VERSION 5.8 ;
BUSBITCHARS "[]" ;
DIVIDERCHAR "/" ;
UNITS
    DATABASE MICRONS 1000 ;
END UNITS

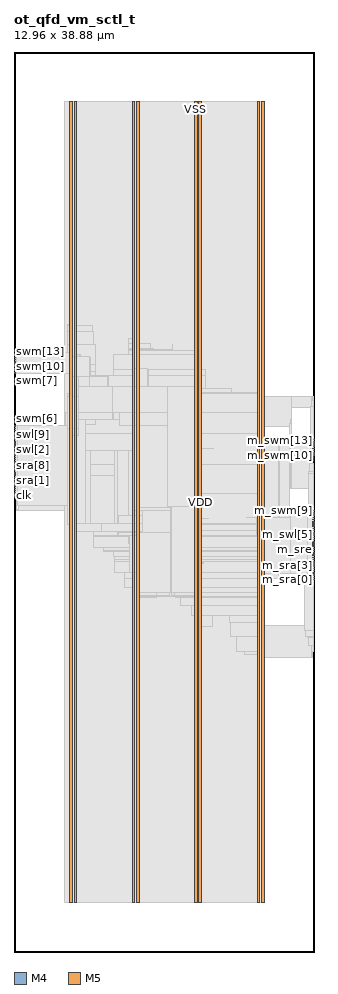
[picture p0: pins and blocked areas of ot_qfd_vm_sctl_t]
MACRO ot_qfd_vm_sctl_t
  FOREIGN ot_qfd_vm_sctl_t 0 0 ;
  CLASS BLOCK ;
  SIZE 12.96 BY 38.88 ;
  PIN clk
    DIRECTION INPUT ;
    USE SIGNAL ;
    PORT
      LAYER M4 ;
        RECT  0 19.728 0.084 19.752 ;
    END
  END clk
  PIN m_sra[0]
    DIRECTION OUTPUT ;
    USE SIGNAL ;
    PORT
      LAYER M4 ;
        RECT  12.876 16.08 12.96 16.104 ;
    END
  END m_sra[0]
  PIN m_sra[1]
    DIRECTION OUTPUT ;
    USE SIGNAL ;
    PORT
      LAYER M4 ;
        RECT  12.876 16.176 12.96 16.2 ;
    END
  END m_sra[1]
  PIN m_sra[2]
    DIRECTION OUTPUT ;
    USE SIGNAL ;
    PORT
      LAYER M4 ;
        RECT  12.876 16.272 12.96 16.296 ;
    END
  END m_sra[2]
  PIN m_sra[3]
    DIRECTION OUTPUT ;
    USE SIGNAL ;
    PORT
      LAYER M4 ;
        RECT  12.876 16.368 12.96 16.392 ;
    END
  END m_sra[3]
  PIN m_sra[4]
    DIRECTION OUTPUT ;
    USE SIGNAL ;
    PORT
      LAYER M4 ;
        RECT  12.876 16.464 12.96 16.488 ;
    END
  END m_sra[4]
  PIN m_sra[5]
    DIRECTION OUTPUT ;
    USE SIGNAL ;
    PORT
      LAYER M4 ;
        RECT  12.876 16.56 12.96 16.584 ;
    END
  END m_sra[5]
  PIN m_sra[6]
    DIRECTION OUTPUT ;
    USE SIGNAL ;
    PORT
      LAYER M4 ;
        RECT  12.876 16.656 12.96 16.68 ;
    END
  END m_sra[6]
  PIN m_sra[7]
    DIRECTION OUTPUT ;
    USE SIGNAL ;
    PORT
      LAYER M4 ;
        RECT  12.876 16.752 12.96 16.776 ;
    END
  END m_sra[7]
  PIN m_sra[8]
    DIRECTION OUTPUT ;
    USE SIGNAL ;
    PORT
      LAYER M4 ;
        RECT  12.876 16.848 12.96 16.872 ;
    END
  END m_sra[8]
  PIN m_sra[9]
    DIRECTION OUTPUT ;
    USE SIGNAL ;
    PORT
      LAYER M4 ;
        RECT  12.876 16.944 12.96 16.968 ;
    END
  END m_sra[9]
  PIN m_sre
    DIRECTION OUTPUT ;
    USE SIGNAL ;
    PORT
      LAYER M4 ;
        RECT  12.876 17.04 12.96 17.064 ;
    END
  END m_sre
  PIN m_swe
    DIRECTION OUTPUT ;
    USE SIGNAL ;
    PORT
      LAYER M4 ;
        RECT  12.876 17.136 12.96 17.16 ;
    END
  END m_swe
  PIN m_swl[0]
    DIRECTION OUTPUT ;
    USE SIGNAL ;
    PORT
      LAYER M4 ;
        RECT  12.876 17.232 12.96 17.256 ;
    END
  END m_swl[0]
  PIN m_swl[1]
    DIRECTION OUTPUT ;
    USE SIGNAL ;
    PORT
      LAYER M4 ;
        RECT  12.876 17.328 12.96 17.352 ;
    END
  END m_swl[1]
  PIN m_swl[2]
    DIRECTION OUTPUT ;
    USE SIGNAL ;
    PORT
      LAYER M4 ;
        RECT  12.876 17.424 12.96 17.448 ;
    END
  END m_swl[2]
  PIN m_swl[3]
    DIRECTION OUTPUT ;
    USE SIGNAL ;
    PORT
      LAYER M4 ;
        RECT  12.876 17.52 12.96 17.544 ;
    END
  END m_swl[3]
  PIN m_swl[4]
    DIRECTION OUTPUT ;
    USE SIGNAL ;
    PORT
      LAYER M4 ;
        RECT  12.876 17.616 12.96 17.64 ;
    END
  END m_swl[4]
  PIN m_swl[5]
    DIRECTION OUTPUT ;
    USE SIGNAL ;
    PORT
      LAYER M4 ;
        RECT  12.876 17.712 12.96 17.736 ;
    END
  END m_swl[5]
  PIN m_swl[6]
    DIRECTION OUTPUT ;
    USE SIGNAL ;
    PORT
      LAYER M4 ;
        RECT  12.876 17.808 12.96 17.832 ;
    END
  END m_swl[6]
  PIN m_swl[7]
    DIRECTION OUTPUT ;
    USE SIGNAL ;
    PORT
      LAYER M4 ;
        RECT  12.876 17.904 12.96 17.928 ;
    END
  END m_swl[7]
  PIN m_swl[8]
    DIRECTION OUTPUT ;
    USE SIGNAL ;
    PORT
      LAYER M4 ;
        RECT  12.876 18 12.96 18.024 ;
    END
  END m_swl[8]
  PIN m_swl[9]
    DIRECTION OUTPUT ;
    USE SIGNAL ;
    PORT
      LAYER M4 ;
        RECT  12.876 18.096 12.96 18.12 ;
    END
  END m_swl[9]
  PIN m_swm[0]
    DIRECTION OUTPUT ;
    USE SIGNAL ;
    PORT
      LAYER M4 ;
        RECT  12.876 18.192 12.96 18.216 ;
    END
  END m_swm[0]
  PIN m_swm[10]
    DIRECTION OUTPUT ;
    USE SIGNAL ;
    PORT
      LAYER M4 ;
        RECT  12.876 21.456 12.96 21.48 ;
    END
  END m_swm[10]
  PIN m_swm[11]
    DIRECTION OUTPUT ;
    USE SIGNAL ;
    PORT
      LAYER M4 ;
        RECT  12.876 21.552 12.96 21.576 ;
    END
  END m_swm[11]
  PIN m_swm[12]
    DIRECTION OUTPUT ;
    USE SIGNAL ;
    PORT
      LAYER M4 ;
        RECT  12.876 21.648 12.96 21.672 ;
    END
  END m_swm[12]
  PIN m_swm[13]
    DIRECTION OUTPUT ;
    USE SIGNAL ;
    PORT
      LAYER M4 ;
        RECT  12.876 21.744 12.96 21.768 ;
    END
  END m_swm[13]
  PIN m_swm[14]
    DIRECTION OUTPUT ;
    USE SIGNAL ;
    PORT
      LAYER M4 ;
        RECT  12.876 21.84 12.96 21.864 ;
    END
  END m_swm[14]
  PIN m_swm[15]
    DIRECTION OUTPUT ;
    USE SIGNAL ;
    PORT
      LAYER M4 ;
        RECT  12.876 21.936 12.96 21.96 ;
    END
  END m_swm[15]
  PIN m_swm[1]
    DIRECTION OUTPUT ;
    USE SIGNAL ;
    PORT
      LAYER M4 ;
        RECT  12.876 18.288 12.96 18.312 ;
    END
  END m_swm[1]
  PIN m_swm[2]
    DIRECTION OUTPUT ;
    USE SIGNAL ;
    PORT
      LAYER M4 ;
        RECT  12.876 18.384 12.96 18.408 ;
    END
  END m_swm[2]
  PIN m_swm[3]
    DIRECTION OUTPUT ;
    USE SIGNAL ;
    PORT
      LAYER M4 ;
        RECT  12.876 18.48 12.96 18.504 ;
    END
  END m_swm[3]
  PIN m_swm[4]
    DIRECTION OUTPUT ;
    USE SIGNAL ;
    PORT
      LAYER M4 ;
        RECT  12.876 18.576 12.96 18.6 ;
    END
  END m_swm[4]
  PIN m_swm[5]
    DIRECTION OUTPUT ;
    USE SIGNAL ;
    PORT
      LAYER M4 ;
        RECT  12.876 18.672 12.96 18.696 ;
    END
  END m_swm[5]
  PIN m_swm[6]
    DIRECTION OUTPUT ;
    USE SIGNAL ;
    PORT
      LAYER M4 ;
        RECT  12.876 18.768 12.96 18.792 ;
    END
  END m_swm[6]
  PIN m_swm[7]
    DIRECTION OUTPUT ;
    USE SIGNAL ;
    PORT
      LAYER M4 ;
        RECT  12.876 18.864 12.96 18.888 ;
    END
  END m_swm[7]
  PIN m_swm[8]
    DIRECTION OUTPUT ;
    USE SIGNAL ;
    PORT
      LAYER M4 ;
        RECT  12.876 18.96 12.96 18.984 ;
    END
  END m_swm[8]
  PIN m_swm[9]
    DIRECTION OUTPUT ;
    USE SIGNAL ;
    PORT
      LAYER M4 ;
        RECT  12.876 19.056 12.96 19.08 ;
    END
  END m_swm[9]
  PIN rst_n
    DIRECTION INPUT ;
    USE SIGNAL ;
    PORT
      LAYER M4 ;
        RECT  0 19.824 0.084 19.848 ;
    END
  END rst_n
  PIN rtg
    DIRECTION OUTPUT ;
    USE SIGNAL ;
    PORT
      LAYER M4 ;
        RECT  12.876 22.032 12.96 22.056 ;
    END
  END rtg
  PIN sra[0]
    DIRECTION INPUT ;
    USE SIGNAL ;
    PORT
      LAYER M4 ;
        RECT  0 19.92 0.084 19.944 ;
    END
  END sra[0]
  PIN sra[1]
    DIRECTION INPUT ;
    USE SIGNAL ;
    PORT
      LAYER M4 ;
        RECT  0 20.016 0.084 20.04 ;
    END
  END sra[1]
  PIN sra[2]
    DIRECTION INPUT ;
    USE SIGNAL ;
    PORT
      LAYER M4 ;
        RECT  0 20.112 0.084 20.136 ;
    END
  END sra[2]
  PIN sra[3]
    DIRECTION INPUT ;
    USE SIGNAL ;
    PORT
      LAYER M4 ;
        RECT  0 20.208 0.084 20.232 ;
    END
  END sra[3]
  PIN sra[4]
    DIRECTION INPUT ;
    USE SIGNAL ;
    PORT
      LAYER M4 ;
        RECT  0 20.304 0.084 20.328 ;
    END
  END sra[4]
  PIN sra[5]
    DIRECTION INPUT ;
    USE SIGNAL ;
    PORT
      LAYER M4 ;
        RECT  0 20.4 0.084 20.424 ;
    END
  END sra[5]
  PIN sra[6]
    DIRECTION INPUT ;
    USE SIGNAL ;
    PORT
      LAYER M4 ;
        RECT  0 20.496 0.084 20.52 ;
    END
  END sra[6]
  PIN sra[7]
    DIRECTION INPUT ;
    USE SIGNAL ;
    PORT
      LAYER M4 ;
        RECT  0 20.592 0.084 20.616 ;
    END
  END sra[7]
  PIN sra[8]
    DIRECTION INPUT ;
    USE SIGNAL ;
    PORT
      LAYER M4 ;
        RECT  0 20.688 0.084 20.712 ;
    END
  END sra[8]
  PIN sra[9]
    DIRECTION INPUT ;
    USE SIGNAL ;
    PORT
      LAYER M4 ;
        RECT  0 20.784 0.084 20.808 ;
    END
  END sra[9]
  PIN sre
    DIRECTION INPUT ;
    USE SIGNAL ;
    PORT
      LAYER M4 ;
        RECT  0 20.88 0.084 20.904 ;
    END
  END sre
  PIN sv
    DIRECTION INPUT ;
    USE SIGNAL ;
    PORT
      LAYER M4 ;
        RECT  0 20.976 0.084 21 ;
    END
  END sv
  PIN svc
    DIRECTION OUTPUT ;
    USE SIGNAL ;
    PORT
      LAYER M4 ;
        RECT  12.876 22.128 12.96 22.152 ;
    END
  END svc
  PIN swe
    DIRECTION INPUT ;
    USE SIGNAL ;
    PORT
      LAYER M4 ;
        RECT  0 21.072 0.084 21.096 ;
    END
  END swe
  PIN swl[0]
    DIRECTION INPUT ;
    USE SIGNAL ;
    PORT
      LAYER M4 ;
        RECT  0 21.168 0.084 21.192 ;
    END
  END swl[0]
  PIN swl[1]
    DIRECTION INPUT ;
    USE SIGNAL ;
    PORT
      LAYER M4 ;
        RECT  0 21.264 0.084 21.288 ;
    END
  END swl[1]
  PIN swl[2]
    DIRECTION INPUT ;
    USE SIGNAL ;
    PORT
      LAYER M4 ;
        RECT  0 21.36 0.084 21.384 ;
    END
  END swl[2]
  PIN swl[3]
    DIRECTION INPUT ;
    USE SIGNAL ;
    PORT
      LAYER M4 ;
        RECT  0 21.456 0.084 21.48 ;
    END
  END swl[3]
  PIN swl[4]
    DIRECTION INPUT ;
    USE SIGNAL ;
    PORT
      LAYER M4 ;
        RECT  0 21.552 0.084 21.576 ;
    END
  END swl[4]
  PIN swl[5]
    DIRECTION INPUT ;
    USE SIGNAL ;
    PORT
      LAYER M4 ;
        RECT  0 21.648 0.084 21.672 ;
    END
  END swl[5]
  PIN swl[6]
    DIRECTION INPUT ;
    USE SIGNAL ;
    PORT
      LAYER M4 ;
        RECT  0 21.744 0.084 21.768 ;
    END
  END swl[6]
  PIN swl[7]
    DIRECTION INPUT ;
    USE SIGNAL ;
    PORT
      LAYER M4 ;
        RECT  0 21.84 0.084 21.864 ;
    END
  END swl[7]
  PIN swl[8]
    DIRECTION INPUT ;
    USE SIGNAL ;
    PORT
      LAYER M4 ;
        RECT  0 21.936 0.084 21.96 ;
    END
  END swl[8]
  PIN swl[9]
    DIRECTION INPUT ;
    USE SIGNAL ;
    PORT
      LAYER M4 ;
        RECT  0 22.032 0.084 22.056 ;
    END
  END swl[9]
  PIN swm[0]
    DIRECTION INPUT ;
    USE SIGNAL ;
    PORT
      LAYER M4 ;
        RECT  0 22.128 0.084 22.152 ;
    END
  END swm[0]
  PIN swm[10]
    DIRECTION INPUT ;
    USE SIGNAL ;
    PORT
      LAYER M4 ;
        RECT  0 25.296 0.084 25.32 ;
    END
  END swm[10]
  PIN swm[11]
    DIRECTION INPUT ;
    USE SIGNAL ;
    PORT
      LAYER M4 ;
        RECT  0 25.392 0.084 25.416 ;
    END
  END swm[11]
  PIN swm[12]
    DIRECTION INPUT ;
    USE SIGNAL ;
    PORT
      LAYER M4 ;
        RECT  0 25.488 0.084 25.512 ;
    END
  END swm[12]
  PIN swm[13]
    DIRECTION INPUT ;
    USE SIGNAL ;
    PORT
      LAYER M4 ;
        RECT  0 25.584 0.084 25.608 ;
    END
  END swm[13]
  PIN swm[14]
    DIRECTION INPUT ;
    USE SIGNAL ;
    PORT
      LAYER M4 ;
        RECT  0 25.68 0.084 25.704 ;
    END
  END swm[14]
  PIN swm[15]
    DIRECTION INPUT ;
    USE SIGNAL ;
    PORT
      LAYER M4 ;
        RECT  0 25.776 0.084 25.8 ;
    END
  END swm[15]
  PIN swm[1]
    DIRECTION INPUT ;
    USE SIGNAL ;
    PORT
      LAYER M4 ;
        RECT  0 22.224 0.084 22.248 ;
    END
  END swm[1]
  PIN swm[2]
    DIRECTION INPUT ;
    USE SIGNAL ;
    PORT
      LAYER M4 ;
        RECT  0 22.32 0.084 22.344 ;
    END
  END swm[2]
  PIN swm[3]
    DIRECTION INPUT ;
    USE SIGNAL ;
    PORT
      LAYER M4 ;
        RECT  0 22.416 0.084 22.44 ;
    END
  END swm[3]
  PIN swm[4]
    DIRECTION INPUT ;
    USE SIGNAL ;
    PORT
      LAYER M4 ;
        RECT  0 22.512 0.084 22.536 ;
    END
  END swm[4]
  PIN swm[5]
    DIRECTION INPUT ;
    USE SIGNAL ;
    PORT
      LAYER M4 ;
        RECT  0 22.608 0.084 22.632 ;
    END
  END swm[5]
  PIN swm[6]
    DIRECTION INPUT ;
    USE SIGNAL ;
    PORT
      LAYER M4 ;
        RECT  0 22.704 0.084 22.728 ;
    END
  END swm[6]
  PIN swm[7]
    DIRECTION INPUT ;
    USE SIGNAL ;
    PORT
      LAYER M4 ;
        RECT  0 25.008 0.084 25.032 ;
    END
  END swm[7]
  PIN swm[8]
    DIRECTION INPUT ;
    USE SIGNAL ;
    PORT
      LAYER M4 ;
        RECT  0 25.104 0.084 25.128 ;
    END
  END swm[8]
  PIN swm[9]
    DIRECTION INPUT ;
    USE SIGNAL ;
    PORT
      LAYER M4 ;
        RECT  0 25.2 0.084 25.224 ;
    END
  END swm[9]
  PIN VDD
    DIRECTION INOUT ;
    USE POWER ;
    PORT
      LAYER M5 ;
        RECT  10.692 2.151 10.812 36.729 ;
        RECT  7.992 2.151 8.112 36.729 ;
        RECT  5.292 2.151 5.412 36.729 ;
        RECT  2.592 2.151 2.712 36.729 ;
    END
  END VDD
  PIN VSS
    DIRECTION INOUT ;
    USE GROUND ;
    PORT
      LAYER M5 ;
        RECT  10.5 2.137 10.62 36.743 ;
        RECT  7.8 2.137 7.92 36.743 ;
        RECT  5.1 2.137 5.22 36.743 ;
        RECT  2.4 2.137 2.52 36.743 ;
    END
  END VSS
  # OT_OBS_CLOSED layer=M5 d_um=1.536 added=9
  OBS
    LAYER RVTN ;
     RECT  2.16 2.16 10.8 2.295 ;
     RECT  2.16 2.565 10.8 2.835 ;
     RECT  2.16 3.105 10.8 3.375 ;
     RECT  2.16 3.645 10.8 3.915 ;
     RECT  2.16 4.185 10.8 4.455 ;
     RECT  2.16 4.725 10.8 4.995 ;
     RECT  2.16 5.265 10.8 5.535 ;
     RECT  2.16 5.805 10.8 6.075 ;
     RECT  2.16 6.345 10.8 6.615 ;
     RECT  2.16 6.885 10.8 7.155 ;
     RECT  2.16 7.425 10.8 7.695 ;
     RECT  2.16 7.965 10.8 8.235 ;
     RECT  2.16 8.505 10.8 8.775 ;
     RECT  2.16 9.045 10.8 9.315 ;
     RECT  2.16 9.585 10.8 9.855 ;
     RECT  2.16 10.125 10.8 10.395 ;
     RECT  2.16 10.665 10.8 10.935 ;
     RECT  2.16 11.205 10.8 11.475 ;
     RECT  2.16 11.745 10.8 12.015 ;
     RECT  2.16 12.285 10.8 12.555 ;
     RECT  2.16 12.825 10.8 13.095 ;
     RECT  2.16 13.365 10.8 13.635 ;
     RECT  2.16 13.905 10.8 14.175 ;
     RECT  2.16 14.445 10.8 14.715 ;
     RECT  2.16 14.985 10.8 15.255 ;
     RECT  2.16 15.525 10.8 15.795 ;
     RECT  2.16 16.065 10.8 16.335 ;
     RECT  2.16 16.605 10.8 16.875 ;
     RECT  2.16 17.145 10.8 17.415 ;
     RECT  2.16 17.685 10.8 17.955 ;
     RECT  2.16 18.225 10.8 18.495 ;
     RECT  2.16 18.765 10.8 19.035 ;
     RECT  2.16 19.305 10.8 19.575 ;
     RECT  2.16 19.845 10.8 20.115 ;
     RECT  2.16 20.385 10.8 20.655 ;
     RECT  2.16 20.925 10.8 21.195 ;
     RECT  2.16 21.465 10.8 21.735 ;
     RECT  2.16 22.005 10.8 22.275 ;
     RECT  2.16 22.545 10.8 22.815 ;
     RECT  2.16 23.085 10.8 23.355 ;
     RECT  2.16 23.625 10.8 23.895 ;
     RECT  2.16 24.165 10.8 24.435 ;
     RECT  2.16 24.705 10.8 24.975 ;
     RECT  2.16 25.245 10.8 25.515 ;
     RECT  2.16 25.785 10.8 26.055 ;
     RECT  2.16 26.325 10.8 26.595 ;
     RECT  2.16 26.865 10.8 27.135 ;
     RECT  2.16 27.405 10.8 27.675 ;
     RECT  2.16 27.945 10.8 28.215 ;
     RECT  2.16 28.485 10.8 28.755 ;
     RECT  2.16 29.025 10.8 29.295 ;
     RECT  2.16 29.565 10.8 29.835 ;
     RECT  2.16 30.105 10.8 30.375 ;
     RECT  2.16 30.645 10.8 30.915 ;
     RECT  2.16 31.185 10.8 31.455 ;
     RECT  2.16 31.725 10.8 31.995 ;
     RECT  2.16 32.265 10.8 32.535 ;
     RECT  2.16 32.805 10.8 33.075 ;
     RECT  2.16 33.345 10.8 33.615 ;
     RECT  2.16 33.885 10.8 34.155 ;
     RECT  2.16 34.425 10.8 34.695 ;
     RECT  2.16 34.965 10.8 35.235 ;
     RECT  2.16 35.505 10.8 35.775 ;
     RECT  2.16 36.045 10.8 36.315 ;
     RECT  2.16 36.585 10.8 36.72 ;
    LAYER RVTP ;
     RECT  2.16 2.295 10.8 2.565 ;
     RECT  2.16 2.835 10.8 3.105 ;
     RECT  2.16 3.375 10.8 3.645 ;
     RECT  2.16 3.915 10.8 4.185 ;
     RECT  2.16 4.455 10.8 4.725 ;
     RECT  2.16 4.995 10.8 5.265 ;
     RECT  2.16 5.535 10.8 5.805 ;
     RECT  2.16 6.075 10.8 6.345 ;
     RECT  2.16 6.615 10.8 6.885 ;
     RECT  2.16 7.155 10.8 7.425 ;
     RECT  2.16 7.695 10.8 7.965 ;
     RECT  2.16 8.235 10.8 8.505 ;
     RECT  2.16 8.775 10.8 9.045 ;
     RECT  2.16 9.315 10.8 9.585 ;
     RECT  2.16 9.855 10.8 10.125 ;
     RECT  2.16 10.395 10.8 10.665 ;
     RECT  2.16 10.935 10.8 11.205 ;
     RECT  2.16 11.475 10.8 11.745 ;
     RECT  2.16 12.015 10.8 12.285 ;
     RECT  2.16 12.555 10.8 12.825 ;
     RECT  2.16 13.095 10.8 13.365 ;
     RECT  2.16 13.635 10.8 13.905 ;
     RECT  2.16 14.175 10.8 14.445 ;
     RECT  2.16 14.715 10.8 14.985 ;
     RECT  2.16 15.255 10.8 15.525 ;
     RECT  2.16 15.795 10.8 16.065 ;
     RECT  2.16 16.335 10.8 16.605 ;
     RECT  2.16 16.875 10.8 17.145 ;
     RECT  2.16 17.415 10.8 17.685 ;
     RECT  2.16 17.955 10.8 18.225 ;
     RECT  2.16 18.495 10.8 18.765 ;
     RECT  2.16 19.035 10.8 19.305 ;
     RECT  2.16 19.575 10.8 19.845 ;
     RECT  2.16 20.115 10.8 20.385 ;
     RECT  2.16 20.655 10.8 20.925 ;
     RECT  2.16 21.195 10.8 21.465 ;
     RECT  2.16 21.735 10.8 22.005 ;
     RECT  2.16 22.275 10.8 22.545 ;
     RECT  2.16 22.815 10.8 23.085 ;
     RECT  2.16 23.355 10.8 23.625 ;
     RECT  2.16 23.895 10.8 24.165 ;
     RECT  2.16 24.435 10.8 24.705 ;
     RECT  2.16 24.975 10.8 25.245 ;
     RECT  2.16 25.515 10.8 25.785 ;
     RECT  2.16 26.055 10.8 26.325 ;
     RECT  2.16 26.595 10.8 26.865 ;
     RECT  2.16 27.135 10.8 27.405 ;
     RECT  2.16 27.675 10.8 27.945 ;
     RECT  2.16 28.215 10.8 28.485 ;
     RECT  2.16 28.755 10.8 29.025 ;
     RECT  2.16 29.295 10.8 29.565 ;
     RECT  2.16 29.835 10.8 30.105 ;
     RECT  2.16 30.375 10.8 30.645 ;
     RECT  2.16 30.915 10.8 31.185 ;
     RECT  2.16 31.455 10.8 31.725 ;
     RECT  2.16 31.995 10.8 32.265 ;
     RECT  2.16 32.535 10.8 32.805 ;
     RECT  2.16 33.075 10.8 33.345 ;
     RECT  2.16 33.615 10.8 33.885 ;
     RECT  2.16 34.155 10.8 34.425 ;
     RECT  2.16 34.695 10.8 34.965 ;
     RECT  2.16 35.235 10.8 35.505 ;
     RECT  2.16 35.775 10.8 36.045 ;
     RECT  2.16 36.315 10.8 36.585 ;
    LAYER M1 ;
     RECT  2.16 2.151 10.8 36.729 ;
    LAYER M2 ;
     RECT  0.103 19.08 0.175 19.098 ;
     RECT  0.175 19.08 0.211 19.368 ;
     RECT  0.103 20.16 0.211 20.178 ;
     RECT  0.211 19.08 2.16 20.178 ;
     RECT  0.535 20.97 2.16 20.988 ;
     RECT  0.103 22.212 2.16 22.23 ;
     RECT  2.16 2.151 10.8 36.729 ;
     RECT  10.8 2.421 10.812 36.459 ;
     RECT  10.812 16.146 11.435 21.924 ;
     RECT  11.435 16.416 11.471 21.924 ;
     RECT  11.471 17.586 11.903 21.924 ;
     RECT  11.903 17.586 11.939 19.224 ;
     RECT  11.903 20.016 11.939 21.924 ;
     RECT  11.939 17.586 11.975 18.414 ;
     RECT  11.939 19.206 11.975 19.224 ;
     RECT  11.939 20.016 11.975 21.564 ;
     RECT  10.812 22.716 11.975 23.994 ;
     RECT  11.471 16.416 12.011 16.794 ;
     RECT  11.975 17.586 12.011 17.604 ;
     RECT  12.011 16.416 12.047 16.434 ;
     RECT  11.975 20.016 12.767 21.492 ;
     RECT  10.812 12.726 12.839 14.094 ;
     RECT  12.767 20.016 12.839 20.034 ;
     RECT  11.975 23.526 12.839 23.994 ;
     RECT  12.811 16.731 12.847 16.749 ;
     RECT  12.767 21.096 12.847 21.492 ;
     RECT  12.839 12.726 12.875 13.014 ;
     RECT  12.847 21.096 12.875 21.879 ;
     RECT  12.839 23.796 12.875 23.994 ;
     RECT  12.839 14.076 12.911 14.094 ;
     RECT  12.847 16.731 12.911 16.866 ;
     RECT  12.875 12.996 12.947 13.014 ;
     RECT  12.911 16.848 12.947 16.866 ;
     RECT  12.775 18.621 12.947 18.639 ;
     RECT  12.875 21.096 12.947 21.114 ;
     RECT  12.875 21.861 12.947 21.879 ;
     RECT  12.875 23.976 12.947 23.994 ;
    LAYER M3 ;
     RECT  2.415 2.143 2.505 2.413 ;
     RECT  5.115 2.143 5.205 2.413 ;
     RECT  7.815 2.143 7.905 2.413 ;
     RECT  10.515 2.143 10.605 2.413 ;
     RECT  10.515 2.413 10.797 12.865 ;
     RECT  9.972 12.865 10.797 12.991 ;
     RECT  12.852 12.721 12.87 12.991 ;
     RECT  12.852 12.991 12.942 13.261 ;
     RECT  12.744 13.261 12.942 13.603 ;
     RECT  9.612 12.991 10.797 13.639 ;
     RECT  12.672 13.603 12.942 13.639 ;
     RECT  12.6 13.639 12.942 13.909 ;
     RECT  7.815 2.413 8.097 14.071 ;
     RECT  9.36 13.639 10.797 14.251 ;
     RECT  7.815 14.071 8.586 14.521 ;
     RECT  9.324 14.251 10.797 14.521 ;
     RECT  7.668 14.521 10.797 14.989 ;
     RECT  5.115 2.413 5.397 15.295 ;
     RECT  7.2 14.989 10.797 15.295 ;
     RECT  5.115 15.295 5.994 15.331 ;
     RECT  6.984 15.295 10.797 15.355 ;
     RECT  5.115 15.331 6.138 15.529 ;
     RECT  6.948 15.355 10.797 15.529 ;
     RECT  5.115 15.529 10.797 15.727 ;
     RECT  4.788 15.727 10.797 16.141 ;
     RECT  4.788 16.141 11.43 16.411 ;
     RECT  12.564 13.909 12.942 16.411 ;
     RECT  4.32 16.411 12.942 16.871 ;
     RECT  4.32 16.871 12.87 16.88 ;
     RECT  4.32 16.88 12.834 16.973 ;
     RECT  4.32 16.973 12.042 17.077 ;
     RECT  12.816 16.973 12.834 17.261 ;
     RECT  4.284 17.077 12.042 17.311 ;
     RECT  3.888 17.311 12.042 17.357 ;
     RECT  3.888 17.357 12.006 17.491 ;
     RECT  3.456 17.491 12.006 17.933 ;
     RECT  3.456 17.933 11.97 17.987 ;
     RECT  2.415 2.413 2.697 18.193 ;
     RECT  3.456 17.987 10.797 18.193 ;
     RECT  2.415 18.193 10.797 18.463 ;
     RECT  12.816 18.187 12.834 18.475 ;
     RECT  2.34 18.463 10.797 18.509 ;
     RECT  12.816 18.475 12.87 18.571 ;
     RECT  12.78 18.571 12.87 18.616 ;
     RECT  11.88 17.987 11.97 18.667 ;
     RECT  12.78 18.616 12.942 18.667 ;
     RECT  11.88 18.667 12.942 18.797 ;
     RECT  11.88 18.797 11.97 19.229 ;
     RECT  0.108 19.075 0.126 19.345 ;
     RECT  0.108 19.345 0.198 19.543 ;
     RECT  11.88 19.229 11.898 19.769 ;
     RECT  2.415 18.509 10.797 19.819 ;
     RECT  12.708 18.797 12.942 20.651 ;
     RECT  12.744 20.651 12.942 20.759 ;
     RECT  0.108 19.543 0.558 20.813 ;
     RECT  2.304 19.819 10.797 21.067 ;
     RECT  12.78 20.759 12.942 21.119 ;
     RECT  0.54 20.813 0.558 21.389 ;
     RECT  12.78 21.119 12.87 21.497 ;
     RECT  11.952 21.451 11.97 21.547 ;
     RECT  12.816 21.497 12.87 21.856 ;
     RECT  11.916 21.547 11.97 22.027 ;
     RECT  0.108 22.207 0.126 22.253 ;
     RECT  2.268 21.067 10.797 22.411 ;
     RECT  11.88 22.027 11.97 22.811 ;
     RECT  11.952 22.811 11.97 23.009 ;
     RECT  2.232 22.411 10.797 23.315 ;
     RECT  12.816 21.856 12.942 23.549 ;
     RECT  12.852 23.549 12.942 23.819 ;
     RECT  12.924 23.819 12.942 23.999 ;
     RECT  2.304 23.315 10.797 24.125 ;
     RECT  2.415 24.125 10.797 24.161 ;
     RECT  2.415 24.161 9.414 24.359 ;
     RECT  2.415 24.359 8.262 24.893 ;
     RECT  2.415 24.893 3.51 25.099 ;
     RECT  4.284 24.893 8.262 25.169 ;
     RECT  2.376 25.099 3.51 25.387 ;
     RECT  0.324 25.675 0.342 25.771 ;
     RECT  0.108 25.771 0.342 25.805 ;
     RECT  4.284 25.169 8.097 25.817 ;
     RECT  0.108 25.805 0.126 25.901 ;
     RECT  4.932 25.817 8.097 25.979 ;
     RECT  4.932 25.979 6.858 26.015 ;
     RECT  4.932 26.015 6.03 26.087 ;
     RECT  2.304 25.387 3.51 26.249 ;
     RECT  6.84 26.015 6.858 26.249 ;
     RECT  4.932 26.087 5.886 26.285 ;
     RECT  4.932 26.285 5.397 26.519 ;
     RECT  2.304 26.249 3.438 26.789 ;
     RECT  2.304 26.789 3.402 27.059 ;
     RECT  2.304 27.059 2.697 27.095 ;
     RECT  2.415 27.095 2.697 36.467 ;
     RECT  5.115 26.519 5.397 36.467 ;
     RECT  7.815 25.979 8.097 36.467 ;
     RECT  10.515 24.161 10.797 36.467 ;
     RECT  2.415 36.467 2.505 36.737 ;
     RECT  5.115 36.467 5.205 36.737 ;
     RECT  7.815 36.467 7.905 36.737 ;
     RECT  10.515 36.467 10.605 36.737 ;
    LAYER M4 ;
     RECT  0.06 25.008 0.097 25.8 ;
     RECT  0.06 19.728 0.133 22.728 ;
     RECT  0.133 19.296 2.329 22.728 ;
     RECT  2.329 18.48 2.408 22.728 ;
     RECT  2.293 23.952 2.408 23.976 ;
     RECT  0.097 25.008 2.408 25.896 ;
     RECT  2.408 2.148 2.512 36.732 ;
     RECT  2.512 2.418 2.704 36.462 ;
     RECT  2.704 24.528 2.845 25.8 ;
     RECT  2.845 24.864 2.873 25.8 ;
     RECT  2.704 18.192 3.089 23.016 ;
     RECT  2.873 24.864 3.292 25.704 ;
     RECT  3.089 18.192 3.305 21.672 ;
     RECT  3.089 22.8 3.521 23.016 ;
     RECT  3.292 24.864 4.021 24.888 ;
     RECT  4.021 24.384 4.061 24.888 ;
     RECT  3.521 22.992 4.261 23.016 ;
     RECT  4.261 22.992 4.309 23.352 ;
     RECT  4.061 24.384 4.309 24.408 ;
     RECT  3.305 18.192 4.345 20.568 ;
     RECT  3.305 21.648 4.345 21.672 ;
     RECT  4.345 18.192 4.46 21.672 ;
     RECT  4.309 22.992 4.549 24.408 ;
     RECT  4.46 18 4.949 21.672 ;
     RECT  4.981 16.416 5.108 16.44 ;
     RECT  4.949 17.664 5.108 21.672 ;
     RECT  4.549 22.752 5.108 24.408 ;
     RECT  5.108 2.148 5.212 36.732 ;
     RECT  5.212 2.418 5.404 36.462 ;
     RECT  5.404 18.144 5.753 20.904 ;
     RECT  5.753 18.72 5.789 20.904 ;
     RECT  5.404 22.128 5.795 25.176 ;
     RECT  5.795 22.128 6.083 24.408 ;
     RECT  6.083 23.328 6.365 24.408 ;
     RECT  6.083 22.128 6.509 22.152 ;
     RECT  5.789 20.544 6.572 20.904 ;
     RECT  6.365 24.384 6.659 24.408 ;
     RECT  5.404 15.36 6.716 15.384 ;
     RECT  6.716 15.36 6.803 15.576 ;
     RECT  5.789 18.72 6.803 19.224 ;
     RECT  6.572 20.544 7.009 21.768 ;
     RECT  5.404 17.136 7.261 17.16 ;
     RECT  6.803 15.36 7.808 15.384 ;
     RECT  7.261 16.8 7.808 17.16 ;
     RECT  6.803 18.72 7.808 18.744 ;
     RECT  7.009 19.92 7.808 21.768 ;
     RECT  6.365 23.328 7.808 23.352 ;
     RECT  7.808 2.148 7.912 36.732 ;
     RECT  7.912 2.418 8.104 36.462 ;
     RECT  8.104 16.8 8.165 16.824 ;
     RECT  8.104 18.72 8.417 18.744 ;
     RECT  8.104 21.744 8.597 21.768 ;
     RECT  10.033 18.768 10.465 18.792 ;
     RECT  10.465 18 10.508 18.792 ;
     RECT  10.508 2.148 10.612 36.732 ;
     RECT  10.612 2.418 10.804 36.462 ;
     RECT  11.869 22.032 11.905 22.056 ;
     RECT  10.804 16.368 11.941 18.792 ;
     RECT  11.905 21.552 11.941 22.056 ;
     RECT  11.941 16.368 12.697 19.08 ;
     RECT  11.941 21.456 12.805 22.056 ;
     RECT  12.697 16.08 12.924 19.08 ;
     RECT  12.805 21.456 12.924 22.152 ;
    LAYER M5 ;
     RECT  2.4 2.137 2.52 2.151 ;
     RECT  5.1 2.137 5.22 2.151 ;
     RECT  7.8 2.137 7.92 2.151 ;
     RECT  10.5 2.137 10.62 2.151 ;
     RECT  5.1 2.151 5.412 16.405 ;
     RECT  4.992 16.405 5.412 17.989 ;
     RECT  4.512 17.989 5.412 18.133 ;
     RECT  4.512 18.133 5.544 18.181 ;
     RECT  3.792 18.181 5.544 18.515 ;
     RECT  4.512 18.515 5.544 18.851 ;
     RECT  5.1 18.851 5.544 19.091 ;
     RECT  6.768 15.541 6.792 19.189 ;
     RECT  6.624 19.189 6.792 19.235 ;
     RECT  0.144 19.285 0.168 20.387 ;
     RECT  2.4 2.151 2.712 22.309 ;
     RECT  2.4 22.309 2.808 22.597 ;
     RECT  5.1 19.091 5.412 22.741 ;
     RECT  6.624 19.235 6.648 22.741 ;
     RECT  4.56 22.741 6.648 23.317 ;
     RECT  2.304 22.597 2.808 23.987 ;
     RECT  4.272 23.317 6.648 24.419 ;
     RECT  2.4 23.987 2.808 24.853 ;
     RECT  5.1 24.419 5.784 25.187 ;
     RECT  2.4 24.853 3.24 25.715 ;
     RECT  2.4 25.715 2.712 36.729 ;
     RECT  5.1 25.187 5.412 36.729 ;
     RECT  7.8 2.151 8.112 36.729 ;
     RECT  10.5 2.151 10.812 36.729 ;
     RECT  2.4 36.729 2.52 36.743 ;
     RECT  5.1 36.729 5.22 36.743 ;
     RECT  7.8 36.729 7.92 36.743 ;
     RECT  10.5 36.729 10.62 36.743 ;
     RECT  5.412 15.541 6.768 18.133 ;
     RECT  6.792 15.541 7.8 19.235 ;
     RECT  5.544 18.133 6.768 19.091 ;
     RECT  2.712 18.181 3.792 18.515 ;
     RECT  5.412 19.091 6.768 19.189 ;
     RECT  5.412 19.189 6.624 22.741 ;
     RECT  6.648 19.235 7.8 24.419 ;
     RECT  2.808 23.317 4.272 24.419 ;
     RECT  2.808 24.419 3.24 24.853 ;
  END
END ot_qfd_vm_sctl_t
END LIBRARY
